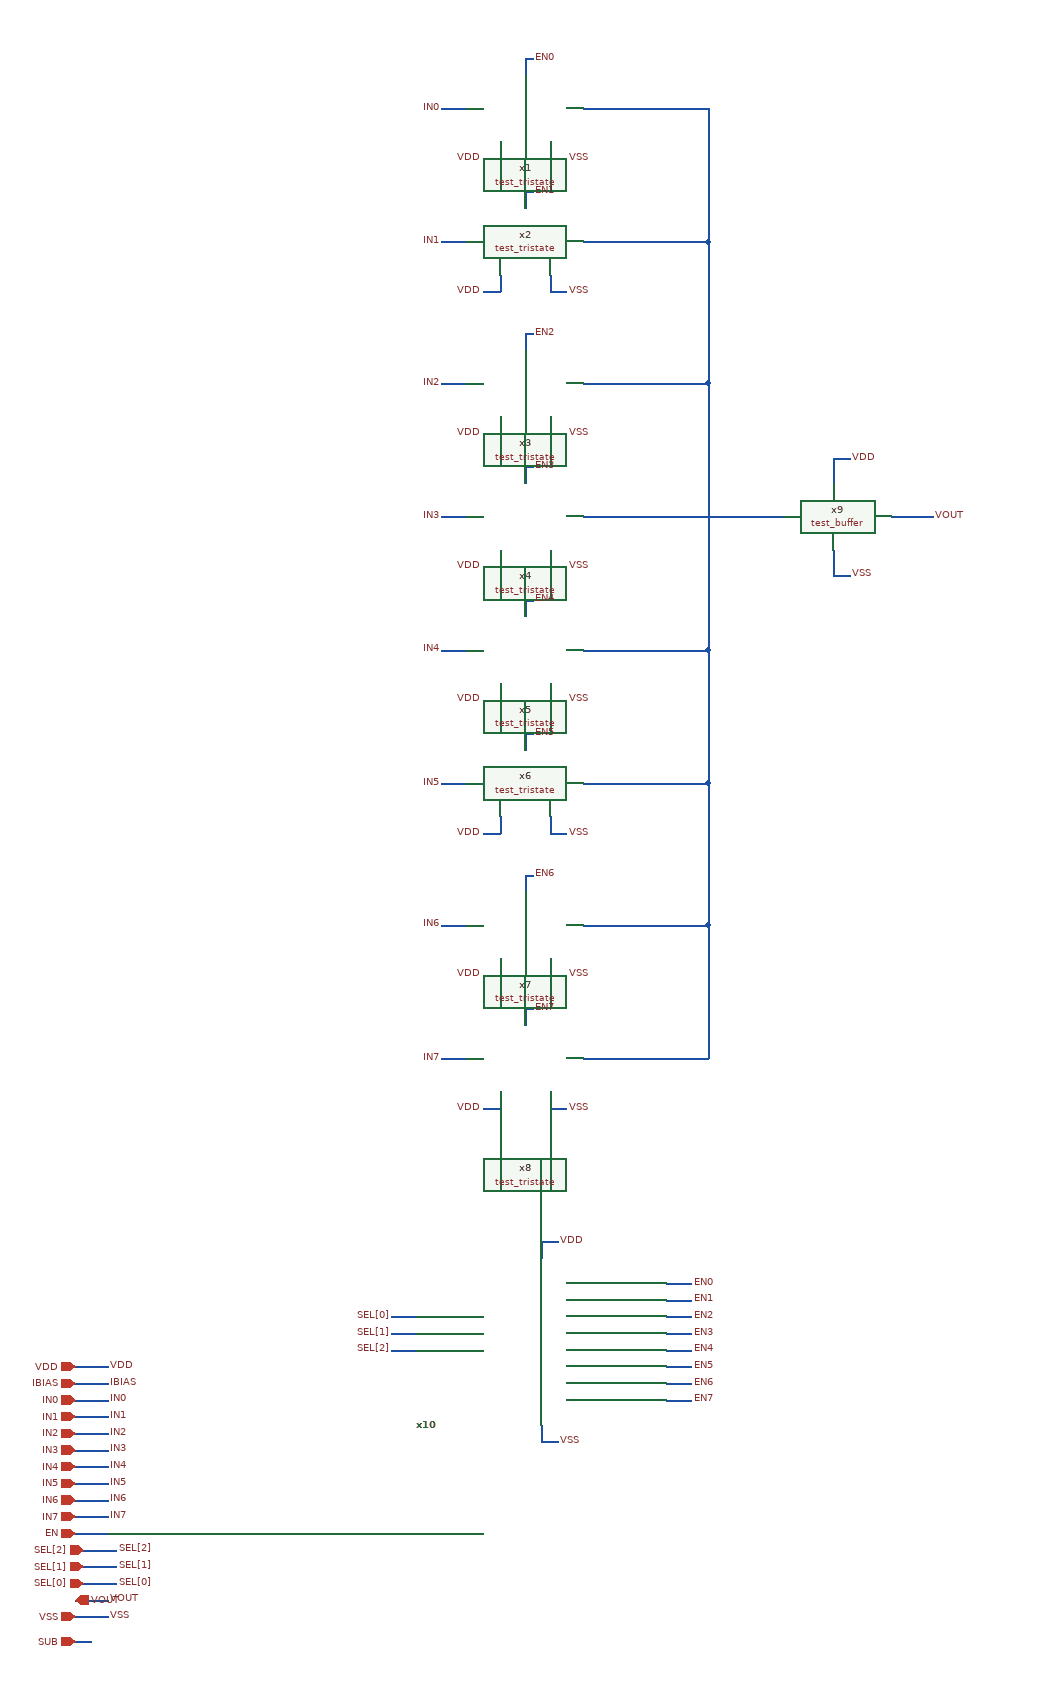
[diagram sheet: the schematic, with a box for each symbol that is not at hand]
v {xschem version=3.4.7 file_version=1.2}
G {}
K {}
V {}
S {}
E {}
N 20 -50 40 -50 {lab=SUB}
N 20 -340 60 -340 {lab=IN0}
N 20 -320 60 -320 {lab=IN1}
N 20 -300 60 -300 {lab=IN2}
N 20 -280 60 -280 {lab=IN3}
N 20 -260 60 -260 {lab=IN4}
N 20 -240 60 -240 {lab=IN5}
N 20 -220 60 -220 {lab=IN6}
N 20 -200 60 -200 {lab=IN7}
N 20 -180 60 -180 {lab=EN}
N 20 -360 60 -360 {lab=IBIAS}
N 20 -380 60 -380 {lab=VDD}
N 30 -160 70 -160 {lab=SEL[2]}
N 20 -100 60 -100 {lab=VOUT}
N 20 -80 60 -80 {lab=VSS}
N 460 -1890 490 -1890 {lab=IN0}
N 560 -1950 560 -1930 {lab=EN0}
N 560 -1950 570 -1950 {lab=EN0}
N 530 -1850 530 -1830 {lab=VDD}
N 510 -1830 530 -1830 {lab=VDD}
N 590 -1850 590 -1830 {lab=VSS}
N 590 -1830 610 -1830 {lab=VSS}
N 460 -1730 490 -1730 {lab=IN1}
N 560 -1790 560 -1770 {lab=EN1}
N 560 -1790 570 -1790 {lab=EN1}
N 530 -1690 530 -1670 {lab=VDD}
N 510 -1670 530 -1670 {lab=VDD}
N 590 -1690 590 -1670 {lab=VSS}
N 590 -1670 610 -1670 {lab=VSS}
N 460 -1560 490 -1560 {lab=IN2}
N 560 -1620 560 -1600 {lab=EN2}
N 560 -1620 570 -1620 {lab=EN2}
N 530 -1520 530 -1500 {lab=VDD}
N 510 -1500 530 -1500 {lab=VDD}
N 590 -1520 590 -1500 {lab=VSS}
N 590 -1500 610 -1500 {lab=VSS}
N 460 -1400 490 -1400 {lab=IN3}
N 560 -1460 560 -1440 {lab=EN3}
N 560 -1460 570 -1460 {lab=EN3}
N 530 -1360 530 -1340 {lab=VDD}
N 510 -1340 530 -1340 {lab=VDD}
N 590 -1360 590 -1340 {lab=VSS}
N 590 -1340 610 -1340 {lab=VSS}
N 460 -1240 490 -1240 {lab=IN4}
N 560 -1300 560 -1280 {lab=EN4}
N 560 -1300 570 -1300 {lab=EN4}
N 530 -1200 530 -1180 {lab=VDD}
N 510 -1180 530 -1180 {lab=VDD}
N 590 -1200 590 -1180 {lab=VSS}
N 590 -1180 610 -1180 {lab=VSS}
N 460 -1080 490 -1080 {lab=IN5}
N 560 -1140 560 -1120 {lab=EN5}
N 560 -1140 570 -1140 {lab=EN5}
N 530 -1040 530 -1020 {lab=VDD}
N 510 -1020 530 -1020 {lab=VDD}
N 590 -1040 590 -1020 {lab=VSS}
N 590 -1020 610 -1020 {lab=VSS}
N 460 -910 490 -910 {lab=IN6}
N 560 -970 560 -950 {lab=EN6}
N 560 -970 570 -970 {lab=EN6}
N 530 -870 530 -850 {lab=VDD}
N 510 -850 530 -850 {lab=VDD}
N 590 -870 590 -850 {lab=VSS}
N 590 -850 610 -850 {lab=VSS}
N 460 -750 490 -750 {lab=IN7}
N 560 -810 560 -790 {lab=EN7}
N 560 -810 570 -810 {lab=EN7}
N 530 -710 530 -690 {lab=VDD}
N 510 -690 530 -690 {lab=VDD}
N 590 -710 590 -690 {lab=VSS}
N 590 -690 610 -690 {lab=VSS}
N 630 -1400 870 -1400 {lab=#net1}
N 630 -1560 780 -1560 {lab=#net1}
N 780 -1560 780 -1400 {lab=#net1}
N 630 -1730 780 -1730 {lab=#net1}
N 780 -1730 780 -1560 {lab=#net1}
N 630 -1890 780 -1890 {lab=#net1}
N 780 -1890 780 -1730 {lab=#net1}
N 630 -1240 780 -1240 {lab=#net1}
N 780 -1400 780 -1240 {lab=#net1}
N 630 -1080 780 -1080 {lab=#net1}
N 780 -1240 780 -1080 {lab=#net1}
N 630 -910 770 -910 {lab=#net1}
N 770 -910 780 -910 {lab=#net1}
N 780 -1080 780 -910 {lab=#net1}
N 630 -750 780 -750 {lab=#net1}
N 780 -910 780 -750 {lab=#net1}
N 930 -1470 930 -1440 {lab=VDD}
N 930 -1470 950 -1470 {lab=VDD}
N 930 -1360 930 -1330 {lab=VSS}
N 930 -1330 950 -1330 {lab=VSS}
N 1000 -1400 1050 -1400 {lab=VOUT}
N 30 -140 70 -140 {lab=SEL[1]}
N 30 -120 70 -120 {lab=SEL[0]}
N 580 -530 580 -510 {lab=VDD}
N 580 -530 600 -530 {lab=VDD}
N 580 -310 580 -290 {lab=VSS}
N 580 -290 600 -290 {lab=VSS}
N 400 -400 430 -400 {lab=SEL[2]}
N 400 -440 430 -440 {lab=SEL[0]}
N 400 -420 430 -420 {lab=SEL[1]}
N 730 -480 760 -480 {lab=#net2}
N 730 -460 760 -460 {lab=#net2}
N 730 -440 760 -440 {lab=#net2}
N 730 -420 760 -420 {lab=#net2}
N 730 -400 760 -400 {lab=#net2}
N 730 -380 760 -380 {lab=#net2}
N 730 -360 760 -360 {lab=#net2}
N 730 -340 760 -340 {lab=#net2}
C {iopin.sym} 20 -380 2 0 {name=p1 lab=VDD}
C {iopin.sym} 20 -80 2 0 {name=p2 lab=VSS}
C {iopin.sym} 20 -50 2 0 {name=p3 lab=SUB}
C {noconn.sym} 40 -50 1 0 {name=l1}
C {iopin.sym} 20 -100 0 1 {name=p4 lab=VOUT}
C {iopin.sym} 20 -360 2 0 {name=p6 lab=IBIAS}
C {ipin.sym} 20 -180 0 0 {name=p5 lab=EN}
C {ipin.sym} 30 -160 0 0 {name=p7 lab=SEL[2]}
C {iopin.sym} 20 -340 2 0 {name=p8 lab=IN0}
C {iopin.sym} 20 -320 2 0 {name=p9 lab=IN1
}
C {iopin.sym} 20 -300 2 0 {name=p10 lab=IN2}
C {iopin.sym} 20 -280 2 0 {name=p11 lab=IN3}
C {iopin.sym} 20 -260 2 0 {name=p12 lab=IN4}
C {iopin.sym} 20 -240 2 0 {name=p13 lab=IN5}
C {iopin.sym} 20 -220 2 0 {name=p14 lab=IN6}
C {iopin.sym} 20 -200 2 0 {name=p15 lab=IN7}
C {libs/core_test/test_tristate/test_tristate.sym} 490 -1850 0 0 {name=x1}
C {lab_pin.sym} 60 -340 0 1 {name=p16 sig_type=std_logic lab=IN0}
C {lab_pin.sym} 60 -320 0 1 {name=p17 sig_type=std_logic lab=IN1}
C {lab_pin.sym} 60 -300 0 1 {name=p18 sig_type=std_logic lab=IN2}
C {lab_pin.sym} 60 -280 0 1 {name=p19 sig_type=std_logic lab=IN3}
C {lab_pin.sym} 60 -260 0 1 {name=p20 sig_type=std_logic lab=IN4}
C {lab_pin.sym} 60 -240 0 1 {name=p21 sig_type=std_logic lab=IN5}
C {lab_pin.sym} 60 -220 0 1 {name=p22 sig_type=std_logic lab=IN6}
C {lab_pin.sym} 60 -200 0 1 {name=p23 sig_type=std_logic lab=IN7}
C {lab_pin.sym} 60 -360 0 1 {name=p25 sig_type=std_logic lab=IBIAS}
C {lab_pin.sym} 60 -380 0 1 {name=p26 sig_type=std_logic lab=VDD}
C {lab_pin.sym} 70 -160 0 1 {name=p27 sig_type=std_logic lab=SEL[2]}
C {lab_pin.sym} 60 -100 0 1 {name=p28 sig_type=std_logic lab=VOUT}
C {lab_pin.sym} 60 -80 0 1 {name=p29 sig_type=std_logic lab=VSS}
C {lab_pin.sym} 460 -1890 0 0 {name=p30 sig_type=std_logic lab=IN0}
C {lab_pin.sym} 510 -1830 0 0 {name=p31 sig_type=std_logic lab=VDD}
C {lab_pin.sym} 610 -1830 0 1 {name=p32 sig_type=std_logic lab=VSS}
C {libs/core_test/test_tristate/test_tristate.sym} 490 -1690 0 0 {name=x2}
C {lab_pin.sym} 460 -1730 0 0 {name=p33 sig_type=std_logic lab=IN1}
C {lab_pin.sym} 510 -1670 0 0 {name=p34 sig_type=std_logic lab=VDD}
C {lab_pin.sym} 610 -1670 0 1 {name=p35 sig_type=std_logic lab=VSS}
C {libs/core_test/test_tristate/test_tristate.sym} 490 -1520 0 0 {name=x3}
C {lab_pin.sym} 460 -1560 0 0 {name=p36 sig_type=std_logic lab=IN2}
C {lab_pin.sym} 510 -1500 0 0 {name=p37 sig_type=std_logic lab=VDD}
C {lab_pin.sym} 610 -1500 0 1 {name=p38 sig_type=std_logic lab=VSS}
C {libs/core_test/test_tristate/test_tristate.sym} 490 -1360 0 0 {name=x4}
C {lab_pin.sym} 460 -1400 0 0 {name=p39 sig_type=std_logic lab=IN3}
C {lab_pin.sym} 510 -1340 0 0 {name=p40 sig_type=std_logic lab=VDD}
C {lab_pin.sym} 610 -1340 0 1 {name=p41 sig_type=std_logic lab=VSS}
C {libs/core_test/test_tristate/test_tristate.sym} 490 -1200 0 0 {name=x5}
C {lab_pin.sym} 460 -1240 0 0 {name=p42 sig_type=std_logic lab=IN4}
C {lab_pin.sym} 510 -1180 0 0 {name=p43 sig_type=std_logic lab=VDD}
C {lab_pin.sym} 610 -1180 0 1 {name=p44 sig_type=std_logic lab=VSS}
C {libs/core_test/test_tristate/test_tristate.sym} 490 -1040 0 0 {name=x6}
C {lab_pin.sym} 460 -1080 0 0 {name=p45 sig_type=std_logic lab=IN5}
C {lab_pin.sym} 510 -1020 0 0 {name=p46 sig_type=std_logic lab=VDD}
C {lab_pin.sym} 610 -1020 0 1 {name=p47 sig_type=std_logic lab=VSS}
C {libs/core_test/test_tristate/test_tristate.sym} 490 -870 0 0 {name=x7}
C {lab_pin.sym} 460 -910 0 0 {name=p48 sig_type=std_logic lab=IN6}
C {lab_pin.sym} 510 -850 0 0 {name=p49 sig_type=std_logic lab=VDD}
C {lab_pin.sym} 610 -850 0 1 {name=p50 sig_type=std_logic lab=VSS}
C {libs/core_test/test_tristate/test_tristate.sym} 490 -710 0 0 {name=x8}
C {lab_pin.sym} 460 -750 0 0 {name=p51 sig_type=std_logic lab=IN7}
C {lab_pin.sym} 510 -690 0 0 {name=p52 sig_type=std_logic lab=VDD}
C {lab_pin.sym} 610 -690 0 1 {name=p53 sig_type=std_logic lab=VSS}
C {libs/core_test/test_buffer/test_buffer.sym} 870 -1360 0 0 {name=x9}
C {lab_pin.sym} 570 -810 0 1 {name=p54 sig_type=std_logic lab=EN7}
C {lab_pin.sym} 570 -970 0 1 {name=p55 sig_type=std_logic lab=EN6}
C {lab_pin.sym} 570 -1140 0 1 {name=p56 sig_type=std_logic lab=EN5}
C {lab_pin.sym} 570 -1300 0 1 {name=p57 sig_type=std_logic lab=EN4}
C {lab_pin.sym} 570 -1460 0 1 {name=p58 sig_type=std_logic lab=EN3}
C {lab_pin.sym} 570 -1620 0 1 {name=p59 sig_type=std_logic lab=EN2}
C {lab_pin.sym} 570 -1790 0 1 {name=p60 sig_type=std_logic lab=EN1}
C {lab_pin.sym} 570 -1950 0 1 {name=p61 sig_type=std_logic lab=EN0}
C {lab_pin.sym} 950 -1470 0 1 {name=p62 sig_type=std_logic lab=VDD}
C {lab_pin.sym} 950 -1330 0 1 {name=p63 sig_type=std_logic lab=VSS}
C {lab_pin.sym} 1050 -1400 0 1 {name=p64 sig_type=std_logic lab=VOUT}
C {ipin.sym} 30 -140 0 0 {name=p24 lab=SEL[1]}
C {lab_pin.sym} 70 -140 0 1 {name=p65 sig_type=std_logic lab=SEL[1]}
C {ipin.sym} 30 -120 0 0 {name=p66 lab=SEL[0]}
C {lab_pin.sym} 70 -120 0 1 {name=p67 sig_type=std_logic lab=SEL[0]}
C {libs/core_test/test_decoder/test_decoder.sym} 430 -310 0 0 {name=x10}
C {lab_pin.sym} 600 -530 0 1 {name=p68 sig_type=std_logic lab=VDD}
C {lab_pin.sym} 600 -290 0 1 {name=p69 sig_type=std_logic lab=VSS}
C {lab_pin.sym} 400 -400 0 0 {name=p70 sig_type=std_logic lab=SEL[2]}
C {lab_pin.sym} 400 -420 0 0 {name=p71 sig_type=std_logic lab=SEL[1]}
C {lab_pin.sym} 400 -440 0 0 {name=p72 sig_type=std_logic lab=SEL[0]}
C {lab_pin.sym} 760 -480 0 1 {name=p73 sig_type=std_logic lab=EN0}
C {lab_pin.sym} 760 -460 0 1 {name=p74 sig_type=std_logic lab=EN1}
C {lab_pin.sym} 760 -440 0 1 {name=p75 sig_type=std_logic lab=EN2}
C {lab_pin.sym} 760 -420 0 1 {name=p76 sig_type=std_logic lab=EN3}
C {lab_pin.sym} 760 -400 0 1 {name=p77 sig_type=std_logic lab=EN4}
C {lab_pin.sym} 760 -380 0 1 {name=p78 sig_type=std_logic lab=EN5}
C {lab_pin.sym} 760 -360 0 1 {name=p79 sig_type=std_logic lab=EN6}
C {lab_pin.sym} 760 -340 0 1 {name=p80 sig_type=std_logic lab=EN7}
